VERSION 5.7 ;
  NOWIREEXTENSIONATPIN ON ;
  DIVIDERCHAR "/" ;
  BUSBITCHARS "[]" ;
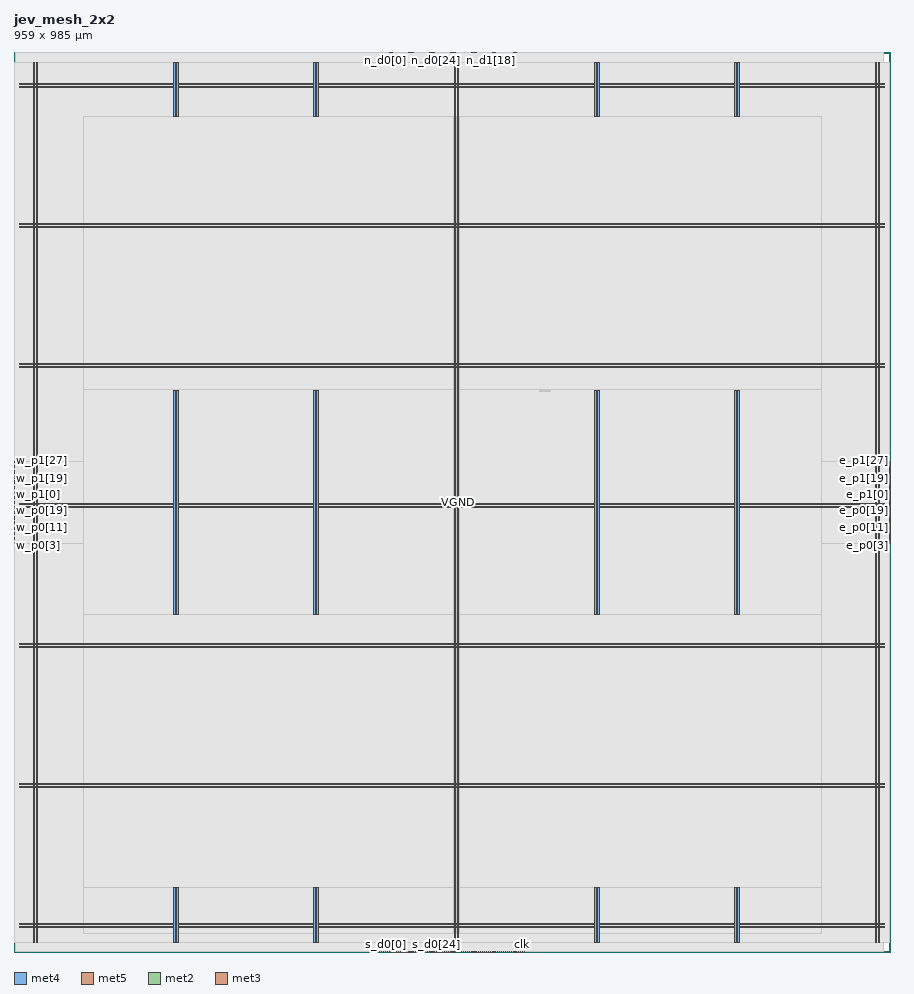
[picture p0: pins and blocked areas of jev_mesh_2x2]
MACRO jev_mesh_2x2
  CLASS BLOCK ;
  FOREIGN jev_mesh_2x2 ;
  ORIGIN 0.000 0.000 ;
  SIZE 959.000 BY 985.000 ;
  PIN VGND
    DIRECTION INOUT ;
    USE GROUND ;
    PORT
      LAYER met4 ;
        RECT 24.340 10.640 25.940 974.000 ;
    END
    PORT
      LAYER met4 ;
        RECT 177.940 10.640 179.540 70.115 ;
    END
    PORT
      LAYER met4 ;
        RECT 177.940 369.845 179.540 614.795 ;
    END
    PORT
      LAYER met4 ;
        RECT 177.940 914.525 179.540 974.000 ;
    END
    PORT
      LAYER met4 ;
        RECT 331.540 10.640 333.140 70.115 ;
    END
    PORT
      LAYER met4 ;
        RECT 331.540 369.845 333.140 614.795 ;
    END
    PORT
      LAYER met4 ;
        RECT 331.540 914.525 333.140 974.000 ;
    END
    PORT
      LAYER met4 ;
        RECT 485.140 10.640 486.740 974.000 ;
    END
    PORT
      LAYER met4 ;
        RECT 638.740 10.640 640.340 70.115 ;
    END
    PORT
      LAYER met4 ;
        RECT 638.740 369.845 640.340 614.795 ;
    END
    PORT
      LAYER met4 ;
        RECT 638.740 914.525 640.340 974.000 ;
    END
    PORT
      LAYER met4 ;
        RECT 792.340 10.640 793.940 70.115 ;
    END
    PORT
      LAYER met4 ;
        RECT 792.340 369.845 793.940 614.795 ;
    END
    PORT
      LAYER met4 ;
        RECT 792.340 914.525 793.940 974.000 ;
    END
    PORT
      LAYER met4 ;
        RECT 945.940 10.640 947.540 974.000 ;
    END
    PORT
      LAYER met5 ;
        RECT 5.520 30.030 953.120 31.630 ;
    END
    PORT
      LAYER met5 ;
        RECT 5.520 183.210 953.120 184.810 ;
    END
    PORT
      LAYER met5 ;
        RECT 5.520 336.390 953.120 337.990 ;
    END
    PORT
      LAYER met5 ;
        RECT 5.520 489.570 953.120 491.170 ;
    END
    PORT
      LAYER met5 ;
        RECT 5.520 642.750 953.120 644.350 ;
    END
    PORT
      LAYER met5 ;
        RECT 5.520 795.930 953.120 797.530 ;
    END
    PORT
      LAYER met5 ;
        RECT 5.520 949.110 953.120 950.710 ;
    END
  END VGND
  PIN VPWR
    DIRECTION INOUT ;
    USE POWER ;
    PORT
      LAYER met4 ;
        RECT 21.040 10.640 22.640 974.000 ;
    END
    PORT
      LAYER met4 ;
        RECT 174.640 10.640 176.240 70.115 ;
    END
    PORT
      LAYER met4 ;
        RECT 174.640 369.845 176.240 614.795 ;
    END
    PORT
      LAYER met4 ;
        RECT 174.640 914.525 176.240 974.000 ;
    END
    PORT
      LAYER met4 ;
        RECT 328.240 10.640 329.840 70.115 ;
    END
    PORT
      LAYER met4 ;
        RECT 328.240 369.845 329.840 614.795 ;
    END
    PORT
      LAYER met4 ;
        RECT 328.240 914.525 329.840 974.000 ;
    END
    PORT
      LAYER met4 ;
        RECT 481.840 10.640 483.440 974.000 ;
    END
    PORT
      LAYER met4 ;
        RECT 635.440 10.640 637.040 70.115 ;
    END
    PORT
      LAYER met4 ;
        RECT 635.440 369.845 637.040 614.795 ;
    END
    PORT
      LAYER met4 ;
        RECT 635.440 914.525 637.040 974.000 ;
    END
    PORT
      LAYER met4 ;
        RECT 789.040 10.640 790.640 70.115 ;
    END
    PORT
      LAYER met4 ;
        RECT 789.040 369.845 790.640 614.795 ;
    END
    PORT
      LAYER met4 ;
        RECT 789.040 914.525 790.640 974.000 ;
    END
    PORT
      LAYER met4 ;
        RECT 942.640 10.640 944.240 974.000 ;
    END
    PORT
      LAYER met5 ;
        RECT 5.520 26.730 953.120 28.330 ;
    END
    PORT
      LAYER met5 ;
        RECT 5.520 179.910 953.120 181.510 ;
    END
    PORT
      LAYER met5 ;
        RECT 5.520 333.090 953.120 334.690 ;
    END
    PORT
      LAYER met5 ;
        RECT 5.520 486.270 953.120 487.870 ;
    END
    PORT
      LAYER met5 ;
        RECT 5.520 639.450 953.120 641.050 ;
    END
    PORT
      LAYER met5 ;
        RECT 5.520 792.630 953.120 794.230 ;
    END
    PORT
      LAYER met5 ;
        RECT 5.520 945.810 953.120 947.410 ;
    END
  END VPWR
  PIN clk
    DIRECTION INPUT ;
    USE SIGNAL ;
    ANTENNAGATEAREA 1.704000 ;
    PORT
      LAYER met2 ;
        RECT 556.230 0.000 556.510 0.280 ;
    END
  END clk
  PIN e_p0[0]
    DIRECTION OUTPUT ;
    USE SIGNAL ;
    ANTENNADIFFAREA 0.383400 ;
    PORT
      LAYER met3 ;
        RECT 958.400 448.840 959.000 449.440 ;
    END
  END e_p0[0]
  PIN e_p0[10]
    DIRECTION OUTPUT ;
    USE SIGNAL ;
    ANTENNADIFFAREA 0.383400 ;
    PORT
      LAYER met3 ;
        RECT 958.400 462.440 959.000 463.040 ;
    END
  END e_p0[10]
  PIN e_p0[11]
    DIRECTION OUTPUT ;
    USE SIGNAL ;
    ANTENNADIFFAREA 0.383400 ;
    PORT
      LAYER met3 ;
        RECT 958.400 463.800 959.000 464.400 ;
    END
  END e_p0[11]
  PIN e_p0[12]
    DIRECTION OUTPUT ;
    USE SIGNAL ;
    ANTENNADIFFAREA 0.383400 ;
    PORT
      LAYER met3 ;
        RECT 958.400 465.160 959.000 465.760 ;
    END
  END e_p0[12]
  PIN e_p0[13]
    DIRECTION OUTPUT ;
    USE SIGNAL ;
    ANTENNADIFFAREA 0.383400 ;
    PORT
      LAYER met3 ;
        RECT 958.400 466.520 959.000 467.120 ;
    END
  END e_p0[13]
  PIN e_p0[14]
    DIRECTION OUTPUT ;
    USE SIGNAL ;
    ANTENNADIFFAREA 0.383400 ;
    PORT
      LAYER met3 ;
        RECT 958.400 467.880 959.000 468.480 ;
    END
  END e_p0[14]
  PIN e_p0[15]
    DIRECTION OUTPUT ;
    USE SIGNAL ;
    ANTENNADIFFAREA 0.383400 ;
    PORT
      LAYER met3 ;
        RECT 958.400 469.240 959.000 469.840 ;
    END
  END e_p0[15]
  PIN e_p0[16]
    DIRECTION OUTPUT ;
    USE SIGNAL ;
    ANTENNADIFFAREA 0.383400 ;
    PORT
      LAYER met3 ;
        RECT 958.400 470.600 959.000 471.200 ;
    END
  END e_p0[16]
  PIN e_p0[17]
    DIRECTION OUTPUT ;
    USE SIGNAL ;
    ANTENNADIFFAREA 0.383400 ;
    PORT
      LAYER met3 ;
        RECT 958.400 471.960 959.000 472.560 ;
    END
  END e_p0[17]
  PIN e_p0[18]
    DIRECTION OUTPUT ;
    USE SIGNAL ;
    ANTENNADIFFAREA 0.383400 ;
    PORT
      LAYER met3 ;
        RECT 958.400 473.320 959.000 473.920 ;
    END
  END e_p0[18]
  PIN e_p0[19]
    DIRECTION OUTPUT ;
    USE SIGNAL ;
    ANTENNADIFFAREA 0.383400 ;
    PORT
      LAYER met3 ;
        RECT 958.400 474.680 959.000 475.280 ;
    END
  END e_p0[19]
  PIN e_p0[1]
    DIRECTION OUTPUT ;
    USE SIGNAL ;
    ANTENNADIFFAREA 0.383400 ;
    PORT
      LAYER met3 ;
        RECT 958.400 450.200 959.000 450.800 ;
    END
  END e_p0[1]
  PIN e_p0[20]
    DIRECTION OUTPUT ;
    USE SIGNAL ;
    ANTENNADIFFAREA 0.383400 ;
    PORT
      LAYER met3 ;
        RECT 958.400 476.040 959.000 476.640 ;
    END
  END e_p0[20]
  PIN e_p0[21]
    DIRECTION OUTPUT ;
    USE SIGNAL ;
    ANTENNADIFFAREA 0.383400 ;
    PORT
      LAYER met3 ;
        RECT 958.400 477.400 959.000 478.000 ;
    END
  END e_p0[21]
  PIN e_p0[22]
    DIRECTION OUTPUT ;
    USE SIGNAL ;
    ANTENNADIFFAREA 0.383400 ;
    PORT
      LAYER met3 ;
        RECT 958.400 478.760 959.000 479.360 ;
    END
  END e_p0[22]
  PIN e_p0[23]
    DIRECTION OUTPUT ;
    USE SIGNAL ;
    ANTENNADIFFAREA 0.383400 ;
    PORT
      LAYER met3 ;
        RECT 958.400 480.120 959.000 480.720 ;
    END
  END e_p0[23]
  PIN e_p0[24]
    DIRECTION OUTPUT ;
    USE SIGNAL ;
    ANTENNADIFFAREA 0.383400 ;
    PORT
      LAYER met3 ;
        RECT 958.400 481.480 959.000 482.080 ;
    END
  END e_p0[24]
  PIN e_p0[25]
    DIRECTION OUTPUT ;
    USE SIGNAL ;
    ANTENNADIFFAREA 0.383400 ;
    PORT
      LAYER met3 ;
        RECT 958.400 482.840 959.000 483.440 ;
    END
  END e_p0[25]
  PIN e_p0[26]
    DIRECTION OUTPUT ;
    USE SIGNAL ;
    ANTENNADIFFAREA 0.383400 ;
    PORT
      LAYER met3 ;
        RECT 958.400 484.200 959.000 484.800 ;
    END
  END e_p0[26]
  PIN e_p0[27]
    DIRECTION OUTPUT ;
    USE SIGNAL ;
    ANTENNADIFFAREA 0.383400 ;
    PORT
      LAYER met3 ;
        RECT 958.400 485.560 959.000 486.160 ;
    END
  END e_p0[27]
  PIN e_p0[28]
    DIRECTION OUTPUT ;
    USE SIGNAL ;
    ANTENNADIFFAREA 0.383400 ;
    PORT
      LAYER met3 ;
        RECT 958.400 486.920 959.000 487.520 ;
    END
  END e_p0[28]
  PIN e_p0[29]
    DIRECTION OUTPUT ;
    USE SIGNAL ;
    ANTENNADIFFAREA 0.383400 ;
    PORT
      LAYER met3 ;
        RECT 958.400 488.280 959.000 488.880 ;
    END
  END e_p0[29]
  PIN e_p0[2]
    DIRECTION OUTPUT ;
    USE SIGNAL ;
    ANTENNADIFFAREA 0.383400 ;
    PORT
      LAYER met3 ;
        RECT 958.400 451.560 959.000 452.160 ;
    END
  END e_p0[2]
  PIN e_p0[30]
    DIRECTION OUTPUT ;
    USE SIGNAL ;
    ANTENNADIFFAREA 0.383400 ;
    PORT
      LAYER met3 ;
        RECT 958.400 489.640 959.000 490.240 ;
    END
  END e_p0[30]
  PIN e_p0[31]
    DIRECTION OUTPUT ;
    USE SIGNAL ;
    ANTENNADIFFAREA 0.383400 ;
    PORT
      LAYER met3 ;
        RECT 958.400 491.000 959.000 491.600 ;
    END
  END e_p0[31]
  PIN e_p0[3]
    DIRECTION OUTPUT ;
    USE SIGNAL ;
    ANTENNADIFFAREA 0.383400 ;
    PORT
      LAYER met3 ;
        RECT 958.400 452.920 959.000 453.520 ;
    END
  END e_p0[3]
  PIN e_p0[4]
    DIRECTION OUTPUT ;
    USE SIGNAL ;
    ANTENNADIFFAREA 0.383400 ;
    PORT
      LAYER met3 ;
        RECT 958.400 454.280 959.000 454.880 ;
    END
  END e_p0[4]
  PIN e_p0[5]
    DIRECTION OUTPUT ;
    USE SIGNAL ;
    ANTENNADIFFAREA 0.383400 ;
    PORT
      LAYER met3 ;
        RECT 958.400 455.640 959.000 456.240 ;
    END
  END e_p0[5]
  PIN e_p0[6]
    DIRECTION OUTPUT ;
    USE SIGNAL ;
    ANTENNADIFFAREA 0.383400 ;
    PORT
      LAYER met3 ;
        RECT 958.400 457.000 959.000 457.600 ;
    END
  END e_p0[6]
  PIN e_p0[7]
    DIRECTION OUTPUT ;
    USE SIGNAL ;
    ANTENNADIFFAREA 0.383400 ;
    PORT
      LAYER met3 ;
        RECT 958.400 458.360 959.000 458.960 ;
    END
  END e_p0[7]
  PIN e_p0[8]
    DIRECTION OUTPUT ;
    USE SIGNAL ;
    ANTENNADIFFAREA 0.383400 ;
    PORT
      LAYER met3 ;
        RECT 958.400 459.720 959.000 460.320 ;
    END
  END e_p0[8]
  PIN e_p0[9]
    DIRECTION OUTPUT ;
    USE SIGNAL ;
    ANTENNADIFFAREA 0.383400 ;
    PORT
      LAYER met3 ;
        RECT 958.400 461.080 959.000 461.680 ;
    END
  END e_p0[9]
  PIN e_p1[0]
    DIRECTION OUTPUT ;
    USE SIGNAL ;
    ANTENNADIFFAREA 0.383400 ;
    PORT
      LAYER met3 ;
        RECT 958.400 492.360 959.000 492.960 ;
    END
  END e_p1[0]
  PIN e_p1[10]
    DIRECTION OUTPUT ;
    USE SIGNAL ;
    ANTENNADIFFAREA 0.383400 ;
    PORT
      LAYER met3 ;
        RECT 958.400 505.960 959.000 506.560 ;
    END
  END e_p1[10]
  PIN e_p1[11]
    DIRECTION OUTPUT ;
    USE SIGNAL ;
    ANTENNADIFFAREA 0.383400 ;
    PORT
      LAYER met3 ;
        RECT 958.400 507.320 959.000 507.920 ;
    END
  END e_p1[11]
  PIN e_p1[12]
    DIRECTION OUTPUT ;
    USE SIGNAL ;
    ANTENNADIFFAREA 0.383400 ;
    PORT
      LAYER met3 ;
        RECT 958.400 508.680 959.000 509.280 ;
    END
  END e_p1[12]
  PIN e_p1[13]
    DIRECTION OUTPUT ;
    USE SIGNAL ;
    ANTENNADIFFAREA 0.383400 ;
    PORT
      LAYER met3 ;
        RECT 958.400 510.040 959.000 510.640 ;
    END
  END e_p1[13]
  PIN e_p1[14]
    DIRECTION OUTPUT ;
    USE SIGNAL ;
    ANTENNADIFFAREA 0.383400 ;
    PORT
      LAYER met3 ;
        RECT 958.400 511.400 959.000 512.000 ;
    END
  END e_p1[14]
  PIN e_p1[15]
    DIRECTION OUTPUT ;
    USE SIGNAL ;
    ANTENNADIFFAREA 0.383400 ;
    PORT
      LAYER met3 ;
        RECT 958.400 512.760 959.000 513.360 ;
    END
  END e_p1[15]
  PIN e_p1[16]
    DIRECTION OUTPUT ;
    USE SIGNAL ;
    ANTENNADIFFAREA 0.383400 ;
    PORT
      LAYER met3 ;
        RECT 958.400 514.120 959.000 514.720 ;
    END
  END e_p1[16]
  PIN e_p1[17]
    DIRECTION OUTPUT ;
    USE SIGNAL ;
    ANTENNADIFFAREA 0.383400 ;
    PORT
      LAYER met3 ;
        RECT 958.400 515.480 959.000 516.080 ;
    END
  END e_p1[17]
  PIN e_p1[18]
    DIRECTION OUTPUT ;
    USE SIGNAL ;
    ANTENNADIFFAREA 0.383400 ;
    PORT
      LAYER met3 ;
        RECT 958.400 516.840 959.000 517.440 ;
    END
  END e_p1[18]
  PIN e_p1[19]
    DIRECTION OUTPUT ;
    USE SIGNAL ;
    ANTENNADIFFAREA 0.383400 ;
    PORT
      LAYER met3 ;
        RECT 958.400 518.200 959.000 518.800 ;
    END
  END e_p1[19]
  PIN e_p1[1]
    DIRECTION OUTPUT ;
    USE SIGNAL ;
    ANTENNADIFFAREA 0.383400 ;
    PORT
      LAYER met3 ;
        RECT 958.400 493.720 959.000 494.320 ;
    END
  END e_p1[1]
  PIN e_p1[20]
    DIRECTION OUTPUT ;
    USE SIGNAL ;
    ANTENNADIFFAREA 0.383400 ;
    PORT
      LAYER met3 ;
        RECT 958.400 519.560 959.000 520.160 ;
    END
  END e_p1[20]
  PIN e_p1[21]
    DIRECTION OUTPUT ;
    USE SIGNAL ;
    ANTENNADIFFAREA 0.383400 ;
    PORT
      LAYER met3 ;
        RECT 958.400 520.920 959.000 521.520 ;
    END
  END e_p1[21]
  PIN e_p1[22]
    DIRECTION OUTPUT ;
    USE SIGNAL ;
    ANTENNADIFFAREA 0.383400 ;
    PORT
      LAYER met3 ;
        RECT 958.400 522.280 959.000 522.880 ;
    END
  END e_p1[22]
  PIN e_p1[23]
    DIRECTION OUTPUT ;
    USE SIGNAL ;
    ANTENNADIFFAREA 0.383400 ;
    PORT
      LAYER met3 ;
        RECT 958.400 523.640 959.000 524.240 ;
    END
  END e_p1[23]
  PIN e_p1[24]
    DIRECTION OUTPUT ;
    USE SIGNAL ;
    ANTENNADIFFAREA 0.383400 ;
    PORT
      LAYER met3 ;
        RECT 958.400 525.000 959.000 525.600 ;
    END
  END e_p1[24]
  PIN e_p1[25]
    DIRECTION OUTPUT ;
    USE SIGNAL ;
    ANTENNADIFFAREA 0.383400 ;
    PORT
      LAYER met3 ;
        RECT 958.400 526.360 959.000 526.960 ;
    END
  END e_p1[25]
  PIN e_p1[26]
    DIRECTION OUTPUT ;
    USE SIGNAL ;
    ANTENNADIFFAREA 0.383400 ;
    PORT
      LAYER met3 ;
        RECT 958.400 527.720 959.000 528.320 ;
    END
  END e_p1[26]
  PIN e_p1[27]
    DIRECTION OUTPUT ;
    USE SIGNAL ;
    ANTENNADIFFAREA 0.383400 ;
    PORT
      LAYER met3 ;
        RECT 958.400 529.080 959.000 529.680 ;
    END
  END e_p1[27]
  PIN e_p1[28]
    DIRECTION OUTPUT ;
    USE SIGNAL ;
    ANTENNADIFFAREA 0.383400 ;
    PORT
      LAYER met3 ;
        RECT 958.400 530.440 959.000 531.040 ;
    END
  END e_p1[28]
  PIN e_p1[29]
    DIRECTION OUTPUT ;
    USE SIGNAL ;
    ANTENNADIFFAREA 0.383400 ;
    PORT
      LAYER met3 ;
        RECT 958.400 531.800 959.000 532.400 ;
    END
  END e_p1[29]
  PIN e_p1[2]
    DIRECTION OUTPUT ;
    USE SIGNAL ;
    ANTENNADIFFAREA 0.383400 ;
    PORT
      LAYER met3 ;
        RECT 958.400 495.080 959.000 495.680 ;
    END
  END e_p1[2]
  PIN e_p1[30]
    DIRECTION OUTPUT ;
    USE SIGNAL ;
    ANTENNADIFFAREA 0.383400 ;
    PORT
      LAYER met3 ;
        RECT 958.400 533.160 959.000 533.760 ;
    END
  END e_p1[30]
  PIN e_p1[31]
    DIRECTION OUTPUT ;
    USE SIGNAL ;
    ANTENNADIFFAREA 0.383400 ;
    PORT
      LAYER met3 ;
        RECT 958.400 534.520 959.000 535.120 ;
    END
  END e_p1[31]
  PIN e_p1[3]
    DIRECTION OUTPUT ;
    USE SIGNAL ;
    ANTENNADIFFAREA 0.383400 ;
    PORT
      LAYER met3 ;
        RECT 958.400 496.440 959.000 497.040 ;
    END
  END e_p1[3]
  PIN e_p1[4]
    DIRECTION OUTPUT ;
    USE SIGNAL ;
    ANTENNADIFFAREA 0.383400 ;
    PORT
      LAYER met3 ;
        RECT 958.400 497.800 959.000 498.400 ;
    END
  END e_p1[4]
  PIN e_p1[5]
    DIRECTION OUTPUT ;
    USE SIGNAL ;
    ANTENNADIFFAREA 0.383400 ;
    PORT
      LAYER met3 ;
        RECT 958.400 499.160 959.000 499.760 ;
    END
  END e_p1[5]
  PIN e_p1[6]
    DIRECTION OUTPUT ;
    USE SIGNAL ;
    ANTENNADIFFAREA 0.383400 ;
    PORT
      LAYER met3 ;
        RECT 958.400 500.520 959.000 501.120 ;
    END
  END e_p1[6]
  PIN e_p1[7]
    DIRECTION OUTPUT ;
    USE SIGNAL ;
    ANTENNADIFFAREA 0.383400 ;
    PORT
      LAYER met3 ;
        RECT 958.400 501.880 959.000 502.480 ;
    END
  END e_p1[7]
  PIN e_p1[8]
    DIRECTION OUTPUT ;
    USE SIGNAL ;
    ANTENNADIFFAREA 0.383400 ;
    PORT
      LAYER met3 ;
        RECT 958.400 503.240 959.000 503.840 ;
    END
  END e_p1[8]
  PIN e_p1[9]
    DIRECTION OUTPUT ;
    USE SIGNAL ;
    ANTENNADIFFAREA 0.383400 ;
    PORT
      LAYER met3 ;
        RECT 958.400 504.600 959.000 505.200 ;
    END
  END e_p1[9]
  PIN e_ready
    DIRECTION INPUT ;
    USE SIGNAL ;
    ANTENNAGATEAREA 0.213000 ;
    PORT
      LAYER met3 ;
        RECT 958.400 535.880 959.000 536.480 ;
    END
  END e_ready
  PIN e_valid
    DIRECTION OUTPUT ;
    USE SIGNAL ;
    ANTENNADIFFAREA 0.383400 ;
    PORT
      LAYER met3 ;
        RECT 958.400 447.480 959.000 448.080 ;
    END
  END e_valid
  PIN n_d0[0]
    DIRECTION INPUT ;
    USE SIGNAL ;
    ANTENNAGATEAREA 0.213000 ;
    PORT
      LAYER met2 ;
        RECT 406.730 984.720 407.010 985.000 ;
    END
  END n_d0[0]
  PIN n_d0[10]
    DIRECTION INPUT ;
    USE SIGNAL ;
    ANTENNAGATEAREA 0.213000 ;
    PORT
      LAYER met2 ;
        RECT 429.730 984.720 430.010 985.000 ;
    END
  END n_d0[10]
  PIN n_d0[11]
    DIRECTION INPUT ;
    USE SIGNAL ;
    ANTENNAGATEAREA 0.213000 ;
    PORT
      LAYER met2 ;
        RECT 432.030 984.720 432.310 985.000 ;
    END
  END n_d0[11]
  PIN n_d0[12]
    DIRECTION INPUT ;
    USE SIGNAL ;
    ANTENNAGATEAREA 0.213000 ;
    PORT
      LAYER met2 ;
        RECT 434.330 984.720 434.610 985.000 ;
    END
  END n_d0[12]
  PIN n_d0[13]
    DIRECTION INPUT ;
    USE SIGNAL ;
    ANTENNAGATEAREA 0.213000 ;
    PORT
      LAYER met2 ;
        RECT 436.630 984.720 436.910 985.000 ;
    END
  END n_d0[13]
  PIN n_d0[14]
    DIRECTION INPUT ;
    USE SIGNAL ;
    ANTENNAGATEAREA 0.213000 ;
    PORT
      LAYER met2 ;
        RECT 438.930 984.720 439.210 985.000 ;
    END
  END n_d0[14]
  PIN n_d0[15]
    DIRECTION INPUT ;
    USE SIGNAL ;
    ANTENNAGATEAREA 0.213000 ;
    PORT
      LAYER met2 ;
        RECT 441.230 984.720 441.510 985.000 ;
    END
  END n_d0[15]
  PIN n_d0[16]
    DIRECTION INPUT ;
    USE SIGNAL ;
    ANTENNAGATEAREA 0.213000 ;
    PORT
      LAYER met2 ;
        RECT 443.530 984.720 443.810 985.000 ;
    END
  END n_d0[16]
  PIN n_d0[17]
    DIRECTION INPUT ;
    USE SIGNAL ;
    ANTENNAGATEAREA 0.213000 ;
    PORT
      LAYER met2 ;
        RECT 445.830 984.720 446.110 985.000 ;
    END
  END n_d0[17]
  PIN n_d0[18]
    DIRECTION INPUT ;
    USE SIGNAL ;
    ANTENNAGATEAREA 0.213000 ;
    PORT
      LAYER met2 ;
        RECT 448.130 984.720 448.410 985.000 ;
    END
  END n_d0[18]
  PIN n_d0[19]
    DIRECTION INPUT ;
    USE SIGNAL ;
    ANTENNAGATEAREA 0.213000 ;
    PORT
      LAYER met2 ;
        RECT 450.430 984.720 450.710 985.000 ;
    END
  END n_d0[19]
  PIN n_d0[1]
    DIRECTION INPUT ;
    USE SIGNAL ;
    ANTENNAGATEAREA 0.213000 ;
    PORT
      LAYER met2 ;
        RECT 409.030 984.720 409.310 985.000 ;
    END
  END n_d0[1]
  PIN n_d0[20]
    DIRECTION INPUT ;
    USE SIGNAL ;
    ANTENNAGATEAREA 0.213000 ;
    PORT
      LAYER met2 ;
        RECT 452.730 984.720 453.010 985.000 ;
    END
  END n_d0[20]
  PIN n_d0[21]
    DIRECTION INPUT ;
    USE SIGNAL ;
    ANTENNAGATEAREA 0.213000 ;
    PORT
      LAYER met2 ;
        RECT 455.030 984.720 455.310 985.000 ;
    END
  END n_d0[21]
  PIN n_d0[22]
    DIRECTION INPUT ;
    USE SIGNAL ;
    ANTENNAGATEAREA 0.213000 ;
    PORT
      LAYER met2 ;
        RECT 457.330 984.720 457.610 985.000 ;
    END
  END n_d0[22]
  PIN n_d0[23]
    DIRECTION INPUT ;
    USE SIGNAL ;
    ANTENNAGATEAREA 0.213000 ;
    PORT
      LAYER met2 ;
        RECT 459.630 984.720 459.910 985.000 ;
    END
  END n_d0[23]
  PIN n_d0[24]
    DIRECTION INPUT ;
    USE SIGNAL ;
    ANTENNAGATEAREA 0.213000 ;
    PORT
      LAYER met2 ;
        RECT 461.930 984.720 462.210 985.000 ;
    END
  END n_d0[24]
  PIN n_d0[25]
    DIRECTION INPUT ;
    USE SIGNAL ;
    ANTENNAGATEAREA 0.213000 ;
    PORT
      LAYER met2 ;
        RECT 464.230 984.720 464.510 985.000 ;
    END
  END n_d0[25]
  PIN n_d0[26]
    DIRECTION INPUT ;
    USE SIGNAL ;
    ANTENNAGATEAREA 0.213000 ;
    PORT
      LAYER met2 ;
        RECT 466.530 984.720 466.810 985.000 ;
    END
  END n_d0[26]
  PIN n_d0[27]
    DIRECTION INPUT ;
    USE SIGNAL ;
    ANTENNAGATEAREA 0.213000 ;
    PORT
      LAYER met2 ;
        RECT 468.830 984.720 469.110 985.000 ;
    END
  END n_d0[27]
  PIN n_d0[28]
    DIRECTION INPUT ;
    USE SIGNAL ;
    ANTENNAGATEAREA 0.213000 ;
    PORT
      LAYER met2 ;
        RECT 471.130 984.720 471.410 985.000 ;
    END
  END n_d0[28]
  PIN n_d0[29]
    DIRECTION INPUT ;
    USE SIGNAL ;
    ANTENNAGATEAREA 0.213000 ;
    PORT
      LAYER met2 ;
        RECT 473.430 984.720 473.710 985.000 ;
    END
  END n_d0[29]
  PIN n_d0[2]
    DIRECTION INPUT ;
    USE SIGNAL ;
    ANTENNAGATEAREA 0.213000 ;
    PORT
      LAYER met2 ;
        RECT 411.330 984.720 411.610 985.000 ;
    END
  END n_d0[2]
  PIN n_d0[30]
    DIRECTION INPUT ;
    USE SIGNAL ;
    ANTENNAGATEAREA 0.213000 ;
    PORT
      LAYER met2 ;
        RECT 475.730 984.720 476.010 985.000 ;
    END
  END n_d0[30]
  PIN n_d0[31]
    DIRECTION INPUT ;
    USE SIGNAL ;
    ANTENNAGATEAREA 0.213000 ;
    PORT
      LAYER met2 ;
        RECT 478.030 984.720 478.310 985.000 ;
    END
  END n_d0[31]
  PIN n_d0[3]
    DIRECTION INPUT ;
    USE SIGNAL ;
    ANTENNAGATEAREA 0.213000 ;
    PORT
      LAYER met2 ;
        RECT 413.630 984.720 413.910 985.000 ;
    END
  END n_d0[3]
  PIN n_d0[4]
    DIRECTION INPUT ;
    USE SIGNAL ;
    ANTENNAGATEAREA 0.213000 ;
    PORT
      LAYER met2 ;
        RECT 415.930 984.720 416.210 985.000 ;
    END
  END n_d0[4]
  PIN n_d0[5]
    DIRECTION INPUT ;
    USE SIGNAL ;
    ANTENNAGATEAREA 0.213000 ;
    PORT
      LAYER met2 ;
        RECT 418.230 984.720 418.510 985.000 ;
    END
  END n_d0[5]
  PIN n_d0[6]
    DIRECTION INPUT ;
    USE SIGNAL ;
    ANTENNAGATEAREA 0.213000 ;
    PORT
      LAYER met2 ;
        RECT 420.530 984.720 420.810 985.000 ;
    END
  END n_d0[6]
  PIN n_d0[7]
    DIRECTION INPUT ;
    USE SIGNAL ;
    ANTENNAGATEAREA 0.213000 ;
    PORT
      LAYER met2 ;
        RECT 422.830 984.720 423.110 985.000 ;
    END
  END n_d0[7]
  PIN n_d0[8]
    DIRECTION INPUT ;
    USE SIGNAL ;
    ANTENNAGATEAREA 0.213000 ;
    PORT
      LAYER met2 ;
        RECT 425.130 984.720 425.410 985.000 ;
    END
  END n_d0[8]
  PIN n_d0[9]
    DIRECTION INPUT ;
    USE SIGNAL ;
    ANTENNAGATEAREA 0.213000 ;
    PORT
      LAYER met2 ;
        RECT 427.430 984.720 427.710 985.000 ;
    END
  END n_d0[9]
  PIN n_d1[0]
    DIRECTION INPUT ;
    USE SIGNAL ;
    ANTENNAGATEAREA 0.213000 ;
    PORT
      LAYER met2 ;
        RECT 480.330 984.720 480.610 985.000 ;
    END
  END n_d1[0]
  PIN n_d1[10]
    DIRECTION INPUT ;
    USE SIGNAL ;
    ANTENNAGATEAREA 0.213000 ;
    PORT
      LAYER met2 ;
        RECT 503.330 984.720 503.610 985.000 ;
    END
  END n_d1[10]
  PIN n_d1[11]
    DIRECTION INPUT ;
    USE SIGNAL ;
    ANTENNAGATEAREA 0.213000 ;
    PORT
      LAYER met2 ;
        RECT 505.630 984.720 505.910 985.000 ;
    END
  END n_d1[11]
  PIN n_d1[12]
    DIRECTION INPUT ;
    USE SIGNAL ;
    ANTENNAGATEAREA 0.213000 ;
    PORT
      LAYER met2 ;
        RECT 507.930 984.720 508.210 985.000 ;
    END
  END n_d1[12]
  PIN n_d1[13]
    DIRECTION INPUT ;
    USE SIGNAL ;
    ANTENNAGATEAREA 0.213000 ;
    PORT
      LAYER met2 ;
        RECT 510.230 984.720 510.510 985.000 ;
    END
  END n_d1[13]
  PIN n_d1[14]
    DIRECTION INPUT ;
    USE SIGNAL ;
    ANTENNAGATEAREA 0.213000 ;
    PORT
      LAYER met2 ;
        RECT 512.530 984.720 512.810 985.000 ;
    END
  END n_d1[14]
  PIN n_d1[15]
    DIRECTION INPUT ;
    USE SIGNAL ;
    ANTENNAGATEAREA 0.213000 ;
    PORT
      LAYER met2 ;
        RECT 514.830 984.720 515.110 985.000 ;
    END
  END n_d1[15]
  PIN n_d1[16]
    DIRECTION INPUT ;
    USE SIGNAL ;
    ANTENNAGATEAREA 0.213000 ;
    PORT
      LAYER met2 ;
        RECT 517.130 984.720 517.410 985.000 ;
    END
  END n_d1[16]
  PIN n_d1[17]
    DIRECTION INPUT ;
    USE SIGNAL ;
    ANTENNAGATEAREA 0.213000 ;
    PORT
      LAYER met2 ;
        RECT 519.430 984.720 519.710 985.000 ;
    END
  END n_d1[17]
  PIN n_d1[18]
    DIRECTION INPUT ;
    USE SIGNAL ;
    ANTENNAGATEAREA 0.213000 ;
    PORT
      LAYER met2 ;
        RECT 521.730 984.720 522.010 985.000 ;
    END
  END n_d1[18]
  PIN n_d1[19]
    DIRECTION INPUT ;
    USE SIGNAL ;
    ANTENNAGATEAREA 0.213000 ;
    PORT
      LAYER met2 ;
        RECT 524.030 984.720 524.310 985.000 ;
    END
  END n_d1[19]
  PIN n_d1[1]
    DIRECTION INPUT ;
    USE SIGNAL ;
    ANTENNAGATEAREA 0.213000 ;
    PORT
      LAYER met2 ;
        RECT 482.630 984.720 482.910 985.000 ;
    END
  END n_d1[1]
  PIN n_d1[20]
    DIRECTION INPUT ;
    USE SIGNAL ;
    ANTENNAGATEAREA 0.213000 ;
    PORT
      LAYER met2 ;
        RECT 526.330 984.720 526.610 985.000 ;
    END
  END n_d1[20]
  PIN n_d1[21]
    DIRECTION INPUT ;
    USE SIGNAL ;
    ANTENNAGATEAREA 0.213000 ;
    PORT
      LAYER met2 ;
        RECT 528.630 984.720 528.910 985.000 ;
    END
  END n_d1[21]
  PIN n_d1[22]
    DIRECTION INPUT ;
    USE SIGNAL ;
    ANTENNAGATEAREA 0.213000 ;
    PORT
      LAYER met2 ;
        RECT 530.930 984.720 531.210 985.000 ;
    END
  END n_d1[22]
  PIN n_d1[23]
    DIRECTION INPUT ;
    USE SIGNAL ;
    ANTENNAGATEAREA 0.213000 ;
    PORT
      LAYER met2 ;
        RECT 533.230 984.720 533.510 985.000 ;
    END
  END n_d1[23]
  PIN n_d1[24]
    DIRECTION INPUT ;
    USE SIGNAL ;
    ANTENNAGATEAREA 0.213000 ;
    PORT
      LAYER met2 ;
        RECT 535.530 984.720 535.810 985.000 ;
    END
  END n_d1[24]
  PIN n_d1[25]
    DIRECTION INPUT ;
    USE SIGNAL ;
    ANTENNAGATEAREA 0.213000 ;
    PORT
      LAYER met2 ;
        RECT 537.830 984.720 538.110 985.000 ;
    END
  END n_d1[25]
  PIN n_d1[26]
    DIRECTION INPUT ;
    USE SIGNAL ;
    ANTENNAGATEAREA 0.213000 ;
    PORT
      LAYER met2 ;
        RECT 540.130 984.720 540.410 985.000 ;
    END
  END n_d1[26]
  PIN n_d1[27]
    DIRECTION INPUT ;
    USE SIGNAL ;
    ANTENNAGATEAREA 0.213000 ;
    PORT
      LAYER met2 ;
        RECT 542.430 984.720 542.710 985.000 ;
    END
  END n_d1[27]
  PIN n_d1[28]
    DIRECTION INPUT ;
    USE SIGNAL ;
    ANTENNAGATEAREA 0.213000 ;
    PORT
      LAYER met2 ;
        RECT 544.730 984.720 545.010 985.000 ;
    END
  END n_d1[28]
  PIN n_d1[29]
    DIRECTION INPUT ;
    USE SIGNAL ;
    ANTENNAGATEAREA 0.159000 ;
    PORT
      LAYER met2 ;
        RECT 547.030 984.720 547.310 985.000 ;
    END
  END n_d1[29]
  PIN n_d1[2]
    DIRECTION INPUT ;
    USE SIGNAL ;
    ANTENNAGATEAREA 0.213000 ;
    PORT
      LAYER met2 ;
        RECT 484.930 984.720 485.210 985.000 ;
    END
  END n_d1[2]
  PIN n_d1[30]
    DIRECTION INPUT ;
    USE SIGNAL ;
    ANTENNAGATEAREA 0.213000 ;
    PORT
      LAYER met2 ;
        RECT 549.330 984.720 549.610 985.000 ;
    END
  END n_d1[30]
  PIN n_d1[31]
    DIRECTION INPUT ;
    USE SIGNAL ;
    ANTENNAGATEAREA 0.159000 ;
    PORT
      LAYER met2 ;
        RECT 551.630 984.720 551.910 985.000 ;
    END
  END n_d1[31]
  PIN n_d1[3]
    DIRECTION INPUT ;
    USE SIGNAL ;
    ANTENNAGATEAREA 0.213000 ;
    PORT
      LAYER met2 ;
        RECT 487.230 984.720 487.510 985.000 ;
    END
  END n_d1[3]
  PIN n_d1[4]
    DIRECTION INPUT ;
    USE SIGNAL ;
    ANTENNAGATEAREA 0.213000 ;
    PORT
      LAYER met2 ;
        RECT 489.530 984.720 489.810 985.000 ;
    END
  END n_d1[4]
  PIN n_d1[5]
    DIRECTION INPUT ;
    USE SIGNAL ;
    ANTENNAGATEAREA 0.213000 ;
    PORT
      LAYER met2 ;
        RECT 491.830 984.720 492.110 985.000 ;
    END
  END n_d1[5]
  PIN n_d1[6]
    DIRECTION INPUT ;
    USE SIGNAL ;
    ANTENNAGATEAREA 0.213000 ;
    PORT
      LAYER met2 ;
        RECT 494.130 984.720 494.410 985.000 ;
    END
  END n_d1[6]
  PIN n_d1[7]
    DIRECTION INPUT ;
    USE SIGNAL ;
    ANTENNAGATEAREA 0.213000 ;
    PORT
      LAYER met2 ;
        RECT 496.430 984.720 496.710 985.000 ;
    END
  END n_d1[7]
  PIN n_d1[8]
    DIRECTION INPUT ;
    USE SIGNAL ;
    ANTENNAGATEAREA 0.213000 ;
    PORT
      LAYER met2 ;
        RECT 498.730 984.720 499.010 985.000 ;
    END
  END n_d1[8]
  PIN n_d1[9]
    DIRECTION INPUT ;
    USE SIGNAL ;
    ANTENNAGATEAREA 0.213000 ;
    PORT
      LAYER met2 ;
        RECT 501.030 984.720 501.310 985.000 ;
    END
  END n_d1[9]
  PIN n_kind[0]
    DIRECTION INPUT ;
    USE SIGNAL ;
    ANTENNAGATEAREA 0.213000 ;
    PORT
      LAYER met2 ;
        RECT 402.130 984.720 402.410 985.000 ;
    END
  END n_kind[0]
  PIN n_kind[1]
    DIRECTION INPUT ;
    USE SIGNAL ;
    ANTENNAGATEAREA 0.213000 ;
    PORT
      LAYER met2 ;
        RECT 404.430 984.720 404.710 985.000 ;
    END
  END n_kind[1]
  PIN n_ready
    DIRECTION OUTPUT ;
    USE SIGNAL ;
    ANTENNADIFFAREA 0.383400 ;
    PORT
      LAYER met2 ;
        RECT 553.930 984.720 554.210 985.000 ;
    END
  END n_ready
  PIN n_valid
    DIRECTION INPUT ;
    USE SIGNAL ;
    ANTENNAGATEAREA 0.213000 ;
    PORT
      LAYER met2 ;
        RECT 399.830 984.720 400.110 985.000 ;
    END
  END n_valid
  PIN rst
    DIRECTION INPUT ;
    USE SIGNAL ;
    ANTENNAGATEAREA 0.159000 ;
    PORT
      LAYER met2 ;
        RECT 558.530 0.000 558.810 0.280 ;
    END
  END rst
  PIN s_d0[0]
    DIRECTION OUTPUT ;
    USE SIGNAL ;
    ANTENNADIFFAREA 0.383400 ;
    PORT
      LAYER met2 ;
        RECT 406.730 0.000 407.010 0.280 ;
    END
  END s_d0[0]
  PIN s_d0[10]
    DIRECTION OUTPUT ;
    USE SIGNAL ;
    ANTENNADIFFAREA 0.383400 ;
    PORT
      LAYER met2 ;
        RECT 429.730 0.000 430.010 0.280 ;
    END
  END s_d0[10]
  PIN s_d0[11]
    DIRECTION OUTPUT ;
    USE SIGNAL ;
    ANTENNADIFFAREA 0.383400 ;
    PORT
      LAYER met2 ;
        RECT 432.030 0.000 432.310 0.280 ;
    END
  END s_d0[11]
  PIN s_d0[12]
    DIRECTION OUTPUT ;
    USE SIGNAL ;
    ANTENNADIFFAREA 0.383400 ;
    PORT
      LAYER met2 ;
        RECT 434.330 0.000 434.610 0.280 ;
    END
  END s_d0[12]
  PIN s_d0[13]
    DIRECTION OUTPUT ;
    USE SIGNAL ;
    ANTENNADIFFAREA 0.383400 ;
    PORT
      LAYER met2 ;
        RECT 436.630 0.000 436.910 0.280 ;
    END
  END s_d0[13]
  PIN s_d0[14]
    DIRECTION OUTPUT ;
    USE SIGNAL ;
    ANTENNADIFFAREA 0.383400 ;
    PORT
      LAYER met2 ;
        RECT 438.930 0.000 439.210 0.280 ;
    END
  END s_d0[14]
  PIN s_d0[15]
    DIRECTION OUTPUT ;
    USE SIGNAL ;
    ANTENNADIFFAREA 0.383400 ;
    PORT
      LAYER met2 ;
        RECT 441.230 0.000 441.510 0.280 ;
    END
  END s_d0[15]
  PIN s_d0[16]
    DIRECTION OUTPUT ;
    USE SIGNAL ;
    ANTENNADIFFAREA 0.383400 ;
    PORT
      LAYER met2 ;
        RECT 443.530 0.000 443.810 0.280 ;
    END
  END s_d0[16]
  PIN s_d0[17]
    DIRECTION OUTPUT ;
    USE SIGNAL ;
    ANTENNADIFFAREA 0.383400 ;
    PORT
      LAYER met2 ;
        RECT 445.830 0.000 446.110 0.280 ;
    END
  END s_d0[17]
  PIN s_d0[18]
    DIRECTION OUTPUT ;
    USE SIGNAL ;
    ANTENNADIFFAREA 0.383400 ;
    PORT
      LAYER met2 ;
        RECT 448.130 0.000 448.410 0.280 ;
    END
  END s_d0[18]
  PIN s_d0[19]
    DIRECTION OUTPUT ;
    USE SIGNAL ;
    ANTENNADIFFAREA 0.383400 ;
    PORT
      LAYER met2 ;
        RECT 450.430 0.000 450.710 0.280 ;
    END
  END s_d0[19]
  PIN s_d0[1]
    DIRECTION OUTPUT ;
    USE SIGNAL ;
    ANTENNADIFFAREA 0.383400 ;
    PORT
      LAYER met2 ;
        RECT 409.030 0.000 409.310 0.280 ;
    END
  END s_d0[1]
  PIN s_d0[20]
    DIRECTION OUTPUT ;
    USE SIGNAL ;
    ANTENNADIFFAREA 0.383400 ;
    PORT
      LAYER met2 ;
        RECT 452.730 0.000 453.010 0.280 ;
    END
  END s_d0[20]
  PIN s_d0[21]
    DIRECTION OUTPUT ;
    USE SIGNAL ;
    ANTENNADIFFAREA 0.383400 ;
    PORT
      LAYER met2 ;
        RECT 455.030 0.000 455.310 0.280 ;
    END
  END s_d0[21]
  PIN s_d0[22]
    DIRECTION OUTPUT ;
    USE SIGNAL ;
    ANTENNADIFFAREA 0.383400 ;
    PORT
      LAYER met2 ;
        RECT 457.330 0.000 457.610 0.280 ;
    END
  END s_d0[22]
  PIN s_d0[23]
    DIRECTION OUTPUT ;
    USE SIGNAL ;
    ANTENNADIFFAREA 0.383400 ;
    PORT
      LAYER met2 ;
        RECT 459.630 0.000 459.910 0.280 ;
    END
  END s_d0[23]
  PIN s_d0[24]
    DIRECTION OUTPUT ;
    USE SIGNAL ;
    ANTENNADIFFAREA 0.383400 ;
    PORT
      LAYER met2 ;
        RECT 461.930 0.000 462.210 0.280 ;
    END
  END s_d0[24]
  PIN s_d0[25]
    DIRECTION OUTPUT ;
    USE SIGNAL ;
    ANTENNADIFFAREA 0.383400 ;
    PORT
      LAYER met2 ;
        RECT 464.230 0.000 464.510 0.280 ;
    END
  END s_d0[25]
  PIN s_d0[26]
    DIRECTION OUTPUT ;
    USE SIGNAL ;
    ANTENNADIFFAREA 0.383400 ;
    PORT
      LAYER met2 ;
        RECT 466.530 0.000 466.810 0.280 ;
    END
  END s_d0[26]
  PIN s_d0[27]
    DIRECTION OUTPUT ;
    USE SIGNAL ;
    ANTENNADIFFAREA 0.383400 ;
    PORT
      LAYER met2 ;
        RECT 468.830 0.000 469.110 0.280 ;
    END
  END s_d0[27]
  PIN s_d0[28]
    DIRECTION OUTPUT ;
    USE SIGNAL ;
    ANTENNADIFFAREA 0.383400 ;
    PORT
      LAYER met2 ;
        RECT 471.130 0.000 471.410 0.280 ;
    END
  END s_d0[28]
  PIN s_d0[29]
    DIRECTION OUTPUT ;
    USE SIGNAL ;
    ANTENNADIFFAREA 0.383400 ;
    PORT
      LAYER met2 ;
        RECT 473.430 0.000 473.710 0.280 ;
    END
  END s_d0[29]
  PIN s_d0[2]
    DIRECTION OUTPUT ;
    USE SIGNAL ;
    ANTENNADIFFAREA 0.383400 ;
    PORT
      LAYER met2 ;
        RECT 411.330 0.000 411.610 0.280 ;
    END
  END s_d0[2]
  PIN s_d0[30]
    DIRECTION OUTPUT ;
    USE SIGNAL ;
    ANTENNADIFFAREA 0.383400 ;
    PORT
      LAYER met2 ;
        RECT 475.730 0.000 476.010 0.280 ;
    END
  END s_d0[30]
  PIN s_d0[31]
    DIRECTION OUTPUT ;
    USE SIGNAL ;
    ANTENNADIFFAREA 0.383400 ;
    PORT
      LAYER met2 ;
        RECT 478.030 0.000 478.310 0.280 ;
    END
  END s_d0[31]
  PIN s_d0[3]
    DIRECTION OUTPUT ;
    USE SIGNAL ;
    ANTENNADIFFAREA 0.383400 ;
    PORT
      LAYER met2 ;
        RECT 413.630 0.000 413.910 0.280 ;
    END
  END s_d0[3]
  PIN s_d0[4]
    DIRECTION OUTPUT ;
    USE SIGNAL ;
    ANTENNADIFFAREA 0.383400 ;
    PORT
      LAYER met2 ;
        RECT 415.930 0.000 416.210 0.280 ;
    END
  END s_d0[4]
  PIN s_d0[5]
    DIRECTION OUTPUT ;
    USE SIGNAL ;
    ANTENNADIFFAREA 0.383400 ;
    PORT
      LAYER met2 ;
        RECT 418.230 0.000 418.510 0.280 ;
    END
  END s_d0[5]
  PIN s_d0[6]
    DIRECTION OUTPUT ;
    USE SIGNAL ;
    ANTENNADIFFAREA 0.383400 ;
    PORT
      LAYER met2 ;
        RECT 420.530 0.000 420.810 0.280 ;
    END
  END s_d0[6]
  PIN s_d0[7]
    DIRECTION OUTPUT ;
    USE SIGNAL ;
    ANTENNADIFFAREA 0.383400 ;
    PORT
      LAYER met2 ;
        RECT 422.830 0.000 423.110 0.280 ;
    END
  END s_d0[7]
  PIN s_d0[8]
    DIRECTION OUTPUT ;
    USE SIGNAL ;
    ANTENNADIFFAREA 0.383400 ;
    PORT
      LAYER met2 ;
        RECT 425.130 0.000 425.410 0.280 ;
    END
  END s_d0[8]
  PIN s_d0[9]
    DIRECTION OUTPUT ;
    USE SIGNAL ;
    ANTENNADIFFAREA 0.383400 ;
    PORT
      LAYER met2 ;
        RECT 427.430 0.000 427.710 0.280 ;
    END
  END s_d0[9]
  PIN s_d1[0]
    DIRECTION OUTPUT ;
    USE SIGNAL ;
    ANTENNADIFFAREA 0.383400 ;
    PORT
      LAYER met2 ;
        RECT 480.330 0.000 480.610 0.280 ;
    END
  END s_d1[0]
  PIN s_d1[10]
    DIRECTION OUTPUT ;
    USE SIGNAL ;
    ANTENNADIFFAREA 0.383400 ;
    PORT
      LAYER met2 ;
        RECT 503.330 0.000 503.610 0.280 ;
    END
  END s_d1[10]
  PIN s_d1[11]
    DIRECTION OUTPUT ;
    USE SIGNAL ;
    ANTENNADIFFAREA 0.383400 ;
    PORT
      LAYER met2 ;
        RECT 505.630 0.000 505.910 0.280 ;
    END
  END s_d1[11]
  PIN s_d1[12]
    DIRECTION OUTPUT ;
    USE SIGNAL ;
    ANTENNADIFFAREA 0.383400 ;
    PORT
      LAYER met2 ;
        RECT 507.930 0.000 508.210 0.280 ;
    END
  END s_d1[12]
  PIN s_d1[13]
    DIRECTION OUTPUT ;
    USE SIGNAL ;
    ANTENNADIFFAREA 0.383400 ;
    PORT
      LAYER met2 ;
        RECT 510.230 0.000 510.510 0.280 ;
    END
  END s_d1[13]
  PIN s_d1[14]
    DIRECTION OUTPUT ;
    USE SIGNAL ;
    ANTENNADIFFAREA 0.383400 ;
    PORT
      LAYER met2 ;
        RECT 512.530 0.000 512.810 0.280 ;
    END
  END s_d1[14]
  PIN s_d1[15]
    DIRECTION OUTPUT ;
    USE SIGNAL ;
    ANTENNADIFFAREA 0.383400 ;
    PORT
      LAYER met2 ;
        RECT 514.830 0.000 515.110 0.280 ;
    END
  END s_d1[15]
  PIN s_d1[16]
    DIRECTION OUTPUT ;
    USE SIGNAL ;
    ANTENNADIFFAREA 0.383400 ;
    PORT
      LAYER met2 ;
        RECT 517.130 0.000 517.410 0.280 ;
    END
  END s_d1[16]
  PIN s_d1[17]
    DIRECTION OUTPUT ;
    USE SIGNAL ;
    ANTENNADIFFAREA 0.383400 ;
    PORT
      LAYER met2 ;
        RECT 519.430 0.000 519.710 0.280 ;
    END
  END s_d1[17]
  PIN s_d1[18]
    DIRECTION OUTPUT ;
    USE SIGNAL ;
    ANTENNADIFFAREA 0.383400 ;
    PORT
      LAYER met2 ;
        RECT 521.730 0.000 522.010 0.280 ;
    END
  END s_d1[18]
  PIN s_d1[19]
    DIRECTION OUTPUT ;
    USE SIGNAL ;
    ANTENNADIFFAREA 0.383400 ;
    PORT
      LAYER met2 ;
        RECT 524.030 0.000 524.310 0.280 ;
    END
  END s_d1[19]
  PIN s_d1[1]
    DIRECTION OUTPUT ;
    USE SIGNAL ;
    ANTENNADIFFAREA 0.383400 ;
    PORT
      LAYER met2 ;
        RECT 482.630 0.000 482.910 0.280 ;
    END
  END s_d1[1]
  PIN s_d1[20]
    DIRECTION OUTPUT ;
    USE SIGNAL ;
    ANTENNADIFFAREA 0.383400 ;
    PORT
      LAYER met2 ;
        RECT 526.330 0.000 526.610 0.280 ;
    END
  END s_d1[20]
  PIN s_d1[21]
    DIRECTION OUTPUT ;
    USE SIGNAL ;
    ANTENNADIFFAREA 0.383400 ;
    PORT
      LAYER met2 ;
        RECT 528.630 0.000 528.910 0.280 ;
    END
  END s_d1[21]
  PIN s_d1[22]
    DIRECTION OUTPUT ;
    USE SIGNAL ;
    ANTENNADIFFAREA 0.383400 ;
    PORT
      LAYER met2 ;
        RECT 530.930 0.000 531.210 0.280 ;
    END
  END s_d1[22]
  PIN s_d1[23]
    DIRECTION OUTPUT ;
    USE SIGNAL ;
    ANTENNADIFFAREA 0.383400 ;
    PORT
      LAYER met2 ;
        RECT 533.230 0.000 533.510 0.280 ;
    END
  END s_d1[23]
  PIN s_d1[24]
    DIRECTION OUTPUT ;
    USE SIGNAL ;
    ANTENNADIFFAREA 0.383400 ;
    PORT
      LAYER met2 ;
        RECT 535.530 0.000 535.810 0.280 ;
    END
  END s_d1[24]
  PIN s_d1[25]
    DIRECTION OUTPUT ;
    USE SIGNAL ;
    ANTENNADIFFAREA 0.383400 ;
    PORT
      LAYER met2 ;
        RECT 537.830 0.000 538.110 0.280 ;
    END
  END s_d1[25]
  PIN s_d1[26]
    DIRECTION OUTPUT ;
    USE SIGNAL ;
    ANTENNADIFFAREA 0.383400 ;
    PORT
      LAYER met2 ;
        RECT 540.130 0.000 540.410 0.280 ;
    END
  END s_d1[26]
  PIN s_d1[27]
    DIRECTION OUTPUT ;
    USE SIGNAL ;
    ANTENNADIFFAREA 0.383400 ;
    PORT
      LAYER met2 ;
        RECT 542.430 0.000 542.710 0.280 ;
    END
  END s_d1[27]
  PIN s_d1[28]
    DIRECTION OUTPUT ;
    USE SIGNAL ;
    ANTENNADIFFAREA 0.383400 ;
    PORT
      LAYER met2 ;
        RECT 544.730 0.000 545.010 0.280 ;
    END
  END s_d1[28]
  PIN s_d1[29]
    DIRECTION OUTPUT ;
    USE SIGNAL ;
    ANTENNADIFFAREA 0.383400 ;
    PORT
      LAYER met2 ;
        RECT 547.030 0.000 547.310 0.280 ;
    END
  END s_d1[29]
  PIN s_d1[2]
    DIRECTION OUTPUT ;
    USE SIGNAL ;
    ANTENNADIFFAREA 0.383400 ;
    PORT
      LAYER met2 ;
        RECT 484.930 0.000 485.210 0.280 ;
    END
  END s_d1[2]
  PIN s_d1[30]
    DIRECTION OUTPUT ;
    USE SIGNAL ;
    ANTENNADIFFAREA 0.383400 ;
    PORT
      LAYER met2 ;
        RECT 549.330 0.000 549.610 0.280 ;
    END
  END s_d1[30]
  PIN s_d1[31]
    DIRECTION OUTPUT ;
    USE SIGNAL ;
    ANTENNADIFFAREA 0.383400 ;
    PORT
      LAYER met2 ;
        RECT 551.630 0.000 551.910 0.280 ;
    END
  END s_d1[31]
  PIN s_d1[3]
    DIRECTION OUTPUT ;
    USE SIGNAL ;
    ANTENNADIFFAREA 0.383400 ;
    PORT
      LAYER met2 ;
        RECT 487.230 0.000 487.510 0.280 ;
    END
  END s_d1[3]
  PIN s_d1[4]
    DIRECTION OUTPUT ;
    USE SIGNAL ;
    ANTENNADIFFAREA 0.383400 ;
    PORT
      LAYER met2 ;
        RECT 489.530 0.000 489.810 0.280 ;
    END
  END s_d1[4]
  PIN s_d1[5]
    DIRECTION OUTPUT ;
    USE SIGNAL ;
    ANTENNADIFFAREA 0.383400 ;
    PORT
      LAYER met2 ;
        RECT 491.830 0.000 492.110 0.280 ;
    END
  END s_d1[5]
  PIN s_d1[6]
    DIRECTION OUTPUT ;
    USE SIGNAL ;
    ANTENNADIFFAREA 0.383400 ;
    PORT
      LAYER met2 ;
        RECT 494.130 0.000 494.410 0.280 ;
    END
  END s_d1[6]
  PIN s_d1[7]
    DIRECTION OUTPUT ;
    USE SIGNAL ;
    ANTENNADIFFAREA 0.383400 ;
    PORT
      LAYER met2 ;
        RECT 496.430 0.000 496.710 0.280 ;
    END
  END s_d1[7]
  PIN s_d1[8]
    DIRECTION OUTPUT ;
    USE SIGNAL ;
    ANTENNADIFFAREA 0.383400 ;
    PORT
      LAYER met2 ;
        RECT 498.730 0.000 499.010 0.280 ;
    END
  END s_d1[8]
  PIN s_d1[9]
    DIRECTION OUTPUT ;
    USE SIGNAL ;
    ANTENNADIFFAREA 0.383400 ;
    PORT
      LAYER met2 ;
        RECT 501.030 0.000 501.310 0.280 ;
    END
  END s_d1[9]
  PIN s_kind[0]
    DIRECTION OUTPUT ;
    USE SIGNAL ;
    ANTENNADIFFAREA 0.383400 ;
    PORT
      LAYER met2 ;
        RECT 402.130 0.000 402.410 0.280 ;
    END
  END s_kind[0]
  PIN s_kind[1]
    DIRECTION OUTPUT ;
    USE SIGNAL ;
    ANTENNADIFFAREA 0.383400 ;
    PORT
      LAYER met2 ;
        RECT 404.430 0.000 404.710 0.280 ;
    END
  END s_kind[1]
  PIN s_ready
    DIRECTION INPUT ;
    USE SIGNAL ;
    ANTENNAGATEAREA 0.196500 ;
    PORT
      LAYER met2 ;
        RECT 553.930 0.000 554.210 0.280 ;
    END
  END s_ready
  PIN s_valid
    DIRECTION OUTPUT ;
    USE SIGNAL ;
    ANTENNADIFFAREA 0.383400 ;
    PORT
      LAYER met2 ;
        RECT 399.830 0.000 400.110 0.280 ;
    END
  END s_valid
  PIN w_p0[0]
    DIRECTION INPUT ;
    USE SIGNAL ;
    ANTENNAGATEAREA 0.213000 ;
    PORT
      LAYER met3 ;
        RECT 0.000 448.840 0.600 449.440 ;
    END
  END w_p0[0]
  PIN w_p0[10]
    DIRECTION INPUT ;
    USE SIGNAL ;
    ANTENNAGATEAREA 0.213000 ;
    PORT
      LAYER met3 ;
        RECT 0.000 462.440 0.600 463.040 ;
    END
  END w_p0[10]
  PIN w_p0[11]
    DIRECTION INPUT ;
    USE SIGNAL ;
    ANTENNAGATEAREA 0.213000 ;
    PORT
      LAYER met3 ;
        RECT 0.000 463.800 0.600 464.400 ;
    END
  END w_p0[11]
  PIN w_p0[12]
    DIRECTION INPUT ;
    USE SIGNAL ;
    ANTENNAGATEAREA 0.213000 ;
    PORT
      LAYER met3 ;
        RECT 0.000 465.160 0.600 465.760 ;
    END
  END w_p0[12]
  PIN w_p0[13]
    DIRECTION INPUT ;
    USE SIGNAL ;
    ANTENNAGATEAREA 0.213000 ;
    PORT
      LAYER met3 ;
        RECT 0.000 466.520 0.600 467.120 ;
    END
  END w_p0[13]
  PIN w_p0[14]
    DIRECTION INPUT ;
    USE SIGNAL ;
    ANTENNAGATEAREA 0.213000 ;
    PORT
      LAYER met3 ;
        RECT 0.000 467.880 0.600 468.480 ;
    END
  END w_p0[14]
  PIN w_p0[15]
    DIRECTION INPUT ;
    USE SIGNAL ;
    ANTENNAGATEAREA 0.213000 ;
    PORT
      LAYER met3 ;
        RECT 0.000 469.240 0.600 469.840 ;
    END
  END w_p0[15]
  PIN w_p0[16]
    DIRECTION INPUT ;
    USE SIGNAL ;
    ANTENNAGATEAREA 0.213000 ;
    PORT
      LAYER met3 ;
        RECT 0.000 470.600 0.600 471.200 ;
    END
  END w_p0[16]
  PIN w_p0[17]
    DIRECTION INPUT ;
    USE SIGNAL ;
    ANTENNAGATEAREA 0.213000 ;
    PORT
      LAYER met3 ;
        RECT 0.000 471.960 0.600 472.560 ;
    END
  END w_p0[17]
  PIN w_p0[18]
    DIRECTION INPUT ;
    USE SIGNAL ;
    ANTENNAGATEAREA 0.213000 ;
    PORT
      LAYER met3 ;
        RECT 0.000 473.320 0.600 473.920 ;
    END
  END w_p0[18]
  PIN w_p0[19]
    DIRECTION INPUT ;
    USE SIGNAL ;
    ANTENNAGATEAREA 0.213000 ;
    PORT
      LAYER met3 ;
        RECT 0.000 474.680 0.600 475.280 ;
    END
  END w_p0[19]
  PIN w_p0[1]
    DIRECTION INPUT ;
    USE SIGNAL ;
    ANTENNAGATEAREA 0.213000 ;
    PORT
      LAYER met3 ;
        RECT 0.000 450.200 0.600 450.800 ;
    END
  END w_p0[1]
  PIN w_p0[20]
    DIRECTION INPUT ;
    USE SIGNAL ;
    ANTENNAGATEAREA 0.213000 ;
    PORT
      LAYER met3 ;
        RECT 0.000 476.040 0.600 476.640 ;
    END
  END w_p0[20]
  PIN w_p0[21]
    DIRECTION INPUT ;
    USE SIGNAL ;
    ANTENNAGATEAREA 0.213000 ;
    PORT
      LAYER met3 ;
        RECT 0.000 477.400 0.600 478.000 ;
    END
  END w_p0[21]
  PIN w_p0[22]
    DIRECTION INPUT ;
    USE SIGNAL ;
    ANTENNAGATEAREA 0.213000 ;
    PORT
      LAYER met3 ;
        RECT 0.000 478.760 0.600 479.360 ;
    END
  END w_p0[22]
  PIN w_p0[23]
    DIRECTION INPUT ;
    USE SIGNAL ;
    ANTENNAGATEAREA 0.213000 ;
    PORT
      LAYER met3 ;
        RECT 0.000 480.120 0.600 480.720 ;
    END
  END w_p0[23]
  PIN w_p0[24]
    DIRECTION INPUT ;
    USE SIGNAL ;
    ANTENNAGATEAREA 0.213000 ;
    PORT
      LAYER met3 ;
        RECT 0.000 481.480 0.600 482.080 ;
    END
  END w_p0[24]
  PIN w_p0[25]
    DIRECTION INPUT ;
    USE SIGNAL ;
    ANTENNAGATEAREA 0.213000 ;
    PORT
      LAYER met3 ;
        RECT 0.000 482.840 0.600 483.440 ;
    END
  END w_p0[25]
  PIN w_p0[26]
    DIRECTION INPUT ;
    USE SIGNAL ;
    ANTENNAGATEAREA 0.213000 ;
    PORT
      LAYER met3 ;
        RECT 0.000 484.200 0.600 484.800 ;
    END
  END w_p0[26]
  PIN w_p0[27]
    DIRECTION INPUT ;
    USE SIGNAL ;
    ANTENNAGATEAREA 0.213000 ;
    PORT
      LAYER met3 ;
        RECT 0.000 485.560 0.600 486.160 ;
    END
  END w_p0[27]
  PIN w_p0[28]
    DIRECTION INPUT ;
    USE SIGNAL ;
    ANTENNAGATEAREA 0.213000 ;
    PORT
      LAYER met3 ;
        RECT 0.000 486.920 0.600 487.520 ;
    END
  END w_p0[28]
  PIN w_p0[29]
    DIRECTION INPUT ;
    USE SIGNAL ;
    ANTENNAGATEAREA 0.213000 ;
    PORT
      LAYER met3 ;
        RECT 0.000 488.280 0.600 488.880 ;
    END
  END w_p0[29]
  PIN w_p0[2]
    DIRECTION INPUT ;
    USE SIGNAL ;
    ANTENNAGATEAREA 0.213000 ;
    PORT
      LAYER met3 ;
        RECT 0.000 451.560 0.600 452.160 ;
    END
  END w_p0[2]
  PIN w_p0[30]
    DIRECTION INPUT ;
    USE SIGNAL ;
    ANTENNAGATEAREA 0.213000 ;
    PORT
      LAYER met3 ;
        RECT 0.000 489.640 0.600 490.240 ;
    END
  END w_p0[30]
  PIN w_p0[31]
    DIRECTION INPUT ;
    USE SIGNAL ;
    ANTENNAGATEAREA 0.213000 ;
    PORT
      LAYER met3 ;
        RECT 0.000 491.000 0.600 491.600 ;
    END
  END w_p0[31]
  PIN w_p0[3]
    DIRECTION INPUT ;
    USE SIGNAL ;
    ANTENNAGATEAREA 0.213000 ;
    PORT
      LAYER met3 ;
        RECT 0.000 452.920 0.600 453.520 ;
    END
  END w_p0[3]
  PIN w_p0[4]
    DIRECTION INPUT ;
    USE SIGNAL ;
    ANTENNAGATEAREA 0.213000 ;
    PORT
      LAYER met3 ;
        RECT 0.000 454.280 0.600 454.880 ;
    END
  END w_p0[4]
  PIN w_p0[5]
    DIRECTION INPUT ;
    USE SIGNAL ;
    ANTENNAGATEAREA 0.213000 ;
    PORT
      LAYER met3 ;
        RECT 0.000 455.640 0.600 456.240 ;
    END
  END w_p0[5]
  PIN w_p0[6]
    DIRECTION INPUT ;
    USE SIGNAL ;
    ANTENNAGATEAREA 0.213000 ;
    PORT
      LAYER met3 ;
        RECT 0.000 457.000 0.600 457.600 ;
    END
  END w_p0[6]
  PIN w_p0[7]
    DIRECTION INPUT ;
    USE SIGNAL ;
    ANTENNAGATEAREA 0.213000 ;
    PORT
      LAYER met3 ;
        RECT 0.000 458.360 0.600 458.960 ;
    END
  END w_p0[7]
  PIN w_p0[8]
    DIRECTION INPUT ;
    USE SIGNAL ;
    ANTENNAGATEAREA 0.213000 ;
    PORT
      LAYER met3 ;
        RECT 0.000 459.720 0.600 460.320 ;
    END
  END w_p0[8]
  PIN w_p0[9]
    DIRECTION INPUT ;
    USE SIGNAL ;
    ANTENNAGATEAREA 0.213000 ;
    PORT
      LAYER met3 ;
        RECT 0.000 461.080 0.600 461.680 ;
    END
  END w_p0[9]
  PIN w_p1[0]
    DIRECTION INPUT ;
    USE SIGNAL ;
    ANTENNAGATEAREA 0.213000 ;
    PORT
      LAYER met3 ;
        RECT 0.000 492.360 0.600 492.960 ;
    END
  END w_p1[0]
  PIN w_p1[10]
    DIRECTION INPUT ;
    USE SIGNAL ;
    ANTENNAGATEAREA 0.213000 ;
    PORT
      LAYER met3 ;
        RECT 0.000 505.960 0.600 506.560 ;
    END
  END w_p1[10]
  PIN w_p1[11]
    DIRECTION INPUT ;
    USE SIGNAL ;
    ANTENNAGATEAREA 0.213000 ;
    PORT
      LAYER met3 ;
        RECT 0.000 507.320 0.600 507.920 ;
    END
  END w_p1[11]
  PIN w_p1[12]
    DIRECTION INPUT ;
    USE SIGNAL ;
    ANTENNAGATEAREA 0.213000 ;
    PORT
      LAYER met3 ;
        RECT 0.000 508.680 0.600 509.280 ;
    END
  END w_p1[12]
  PIN w_p1[13]
    DIRECTION INPUT ;
    USE SIGNAL ;
    ANTENNAGATEAREA 0.213000 ;
    PORT
      LAYER met3 ;
        RECT 0.000 510.040 0.600 510.640 ;
    END
  END w_p1[13]
  PIN w_p1[14]
    DIRECTION INPUT ;
    USE SIGNAL ;
    ANTENNAGATEAREA 0.213000 ;
    PORT
      LAYER met3 ;
        RECT 0.000 511.400 0.600 512.000 ;
    END
  END w_p1[14]
  PIN w_p1[15]
    DIRECTION INPUT ;
    USE SIGNAL ;
    ANTENNAGATEAREA 0.213000 ;
    PORT
      LAYER met3 ;
        RECT 0.000 512.760 0.600 513.360 ;
    END
  END w_p1[15]
  PIN w_p1[16]
    DIRECTION INPUT ;
    USE SIGNAL ;
    ANTENNAGATEAREA 0.213000 ;
    PORT
      LAYER met3 ;
        RECT 0.000 514.120 0.600 514.720 ;
    END
  END w_p1[16]
  PIN w_p1[17]
    DIRECTION INPUT ;
    USE SIGNAL ;
    ANTENNAGATEAREA 0.213000 ;
    PORT
      LAYER met3 ;
        RECT 0.000 515.480 0.600 516.080 ;
    END
  END w_p1[17]
  PIN w_p1[18]
    DIRECTION INPUT ;
    USE SIGNAL ;
    ANTENNAGATEAREA 0.213000 ;
    PORT
      LAYER met3 ;
        RECT 0.000 516.840 0.600 517.440 ;
    END
  END w_p1[18]
  PIN w_p1[19]
    DIRECTION INPUT ;
    USE SIGNAL ;
    ANTENNAGATEAREA 0.213000 ;
    PORT
      LAYER met3 ;
        RECT 0.000 518.200 0.600 518.800 ;
    END
  END w_p1[19]
  PIN w_p1[1]
    DIRECTION INPUT ;
    USE SIGNAL ;
    ANTENNAGATEAREA 0.213000 ;
    PORT
      LAYER met3 ;
        RECT 0.000 493.720 0.600 494.320 ;
    END
  END w_p1[1]
  PIN w_p1[20]
    DIRECTION INPUT ;
    USE SIGNAL ;
    ANTENNAGATEAREA 0.213000 ;
    PORT
      LAYER met3 ;
        RECT 0.000 519.560 0.600 520.160 ;
    END
  END w_p1[20]
  PIN w_p1[21]
    DIRECTION INPUT ;
    USE SIGNAL ;
    ANTENNAGATEAREA 0.213000 ;
    PORT
      LAYER met3 ;
        RECT 0.000 520.920 0.600 521.520 ;
    END
  END w_p1[21]
  PIN w_p1[22]
    DIRECTION INPUT ;
    USE SIGNAL ;
    ANTENNAGATEAREA 0.213000 ;
    PORT
      LAYER met3 ;
        RECT 0.000 522.280 0.600 522.880 ;
    END
  END w_p1[22]
  PIN w_p1[23]
    DIRECTION INPUT ;
    USE SIGNAL ;
    ANTENNAGATEAREA 0.213000 ;
    PORT
      LAYER met3 ;
        RECT 0.000 523.640 0.600 524.240 ;
    END
  END w_p1[23]
  PIN w_p1[24]
    DIRECTION INPUT ;
    USE SIGNAL ;
    ANTENNAGATEAREA 0.213000 ;
    PORT
      LAYER met3 ;
        RECT 0.000 525.000 0.600 525.600 ;
    END
  END w_p1[24]
  PIN w_p1[25]
    DIRECTION INPUT ;
    USE SIGNAL ;
    ANTENNAGATEAREA 0.213000 ;
    PORT
      LAYER met3 ;
        RECT 0.000 526.360 0.600 526.960 ;
    END
  END w_p1[25]
  PIN w_p1[26]
    DIRECTION INPUT ;
    USE SIGNAL ;
    ANTENNAGATEAREA 0.213000 ;
    PORT
      LAYER met3 ;
        RECT 0.000 527.720 0.600 528.320 ;
    END
  END w_p1[26]
  PIN w_p1[27]
    DIRECTION INPUT ;
    USE SIGNAL ;
    ANTENNAGATEAREA 0.213000 ;
    PORT
      LAYER met3 ;
        RECT 0.000 529.080 0.600 529.680 ;
    END
  END w_p1[27]
  PIN w_p1[28]
    DIRECTION INPUT ;
    USE SIGNAL ;
    ANTENNAGATEAREA 0.213000 ;
    PORT
      LAYER met3 ;
        RECT 0.000 530.440 0.600 531.040 ;
    END
  END w_p1[28]
  PIN w_p1[29]
    DIRECTION INPUT ;
    USE SIGNAL ;
    ANTENNAGATEAREA 0.213000 ;
    PORT
      LAYER met3 ;
        RECT 0.000 531.800 0.600 532.400 ;
    END
  END w_p1[29]
  PIN w_p1[2]
    DIRECTION INPUT ;
    USE SIGNAL ;
    ANTENNAGATEAREA 0.213000 ;
    PORT
      LAYER met3 ;
        RECT 0.000 495.080 0.600 495.680 ;
    END
  END w_p1[2]
  PIN w_p1[30]
    DIRECTION INPUT ;
    USE SIGNAL ;
    ANTENNAGATEAREA 0.213000 ;
    PORT
      LAYER met3 ;
        RECT 0.000 533.160 0.600 533.760 ;
    END
  END w_p1[30]
  PIN w_p1[31]
    DIRECTION INPUT ;
    USE SIGNAL ;
    ANTENNAGATEAREA 0.213000 ;
    PORT
      LAYER met3 ;
        RECT 0.000 534.520 0.600 535.120 ;
    END
  END w_p1[31]
  PIN w_p1[3]
    DIRECTION INPUT ;
    USE SIGNAL ;
    ANTENNAGATEAREA 0.213000 ;
    PORT
      LAYER met3 ;
        RECT 0.000 496.440 0.600 497.040 ;
    END
  END w_p1[3]
  PIN w_p1[4]
    DIRECTION INPUT ;
    USE SIGNAL ;
    ANTENNAGATEAREA 0.213000 ;
    PORT
      LAYER met3 ;
        RECT 0.000 497.800 0.600 498.400 ;
    END
  END w_p1[4]
  PIN w_p1[5]
    DIRECTION INPUT ;
    USE SIGNAL ;
    ANTENNAGATEAREA 0.213000 ;
    PORT
      LAYER met3 ;
        RECT 0.000 499.160 0.600 499.760 ;
    END
  END w_p1[5]
  PIN w_p1[6]
    DIRECTION INPUT ;
    USE SIGNAL ;
    ANTENNAGATEAREA 0.213000 ;
    PORT
      LAYER met3 ;
        RECT 0.000 500.520 0.600 501.120 ;
    END
  END w_p1[6]
  PIN w_p1[7]
    DIRECTION INPUT ;
    USE SIGNAL ;
    ANTENNAGATEAREA 0.213000 ;
    PORT
      LAYER met3 ;
        RECT 0.000 501.880 0.600 502.480 ;
    END
  END w_p1[7]
  PIN w_p1[8]
    DIRECTION INPUT ;
    USE SIGNAL ;
    ANTENNAGATEAREA 0.213000 ;
    PORT
      LAYER met3 ;
        RECT 0.000 503.240 0.600 503.840 ;
    END
  END w_p1[8]
  PIN w_p1[9]
    DIRECTION INPUT ;
    USE SIGNAL ;
    ANTENNAGATEAREA 0.213000 ;
    PORT
      LAYER met3 ;
        RECT 0.000 504.600 0.600 505.200 ;
    END
  END w_p1[9]
  PIN w_ready
    DIRECTION OUTPUT ;
    USE SIGNAL ;
    ANTENNADIFFAREA 0.383400 ;
    PORT
      LAYER met3 ;
        RECT 0.000 535.880 0.600 536.480 ;
    END
  END w_ready
  PIN w_valid
    DIRECTION INPUT ;
    USE SIGNAL ;
    ANTENNAGATEAREA 0.213000 ;
    PORT
      LAYER met3 ;
        RECT 0.000 447.480 0.600 448.080 ;
    END
  END w_valid
  OBS
      LAYER nwell ;
        RECT 5.330 10.795 953.310 973.845 ;
      LAYER li1 ;
        RECT 5.520 10.795 953.120 973.845 ;
      LAYER met1 ;
        RECT 1.450 10.240 953.120 974.000 ;
      LAYER met2 ;
        RECT 1.470 984.440 399.550 984.720 ;
        RECT 400.390 984.440 401.850 984.720 ;
        RECT 402.690 984.440 404.150 984.720 ;
        RECT 404.990 984.440 406.450 984.720 ;
        RECT 407.290 984.440 408.750 984.720 ;
        RECT 409.590 984.440 411.050 984.720 ;
        RECT 411.890 984.440 413.350 984.720 ;
        RECT 414.190 984.440 415.650 984.720 ;
        RECT 416.490 984.440 417.950 984.720 ;
        RECT 418.790 984.440 420.250 984.720 ;
        RECT 421.090 984.440 422.550 984.720 ;
        RECT 423.390 984.440 424.850 984.720 ;
        RECT 425.690 984.440 427.150 984.720 ;
        RECT 427.990 984.440 429.450 984.720 ;
        RECT 430.290 984.440 431.750 984.720 ;
        RECT 432.590 984.440 434.050 984.720 ;
        RECT 434.890 984.440 436.350 984.720 ;
        RECT 437.190 984.440 438.650 984.720 ;
        RECT 439.490 984.440 440.950 984.720 ;
        RECT 441.790 984.440 443.250 984.720 ;
        RECT 444.090 984.440 445.550 984.720 ;
        RECT 446.390 984.440 447.850 984.720 ;
        RECT 448.690 984.440 450.150 984.720 ;
        RECT 450.990 984.440 452.450 984.720 ;
        RECT 453.290 984.440 454.750 984.720 ;
        RECT 455.590 984.440 457.050 984.720 ;
        RECT 457.890 984.440 459.350 984.720 ;
        RECT 460.190 984.440 461.650 984.720 ;
        RECT 462.490 984.440 463.950 984.720 ;
        RECT 464.790 984.440 466.250 984.720 ;
        RECT 467.090 984.440 468.550 984.720 ;
        RECT 469.390 984.440 470.850 984.720 ;
        RECT 471.690 984.440 473.150 984.720 ;
        RECT 473.990 984.440 475.450 984.720 ;
        RECT 476.290 984.440 477.750 984.720 ;
        RECT 478.590 984.440 480.050 984.720 ;
        RECT 480.890 984.440 482.350 984.720 ;
        RECT 483.190 984.440 484.650 984.720 ;
        RECT 485.490 984.440 486.950 984.720 ;
        RECT 487.790 984.440 489.250 984.720 ;
        RECT 490.090 984.440 491.550 984.720 ;
        RECT 492.390 984.440 493.850 984.720 ;
        RECT 494.690 984.440 496.150 984.720 ;
        RECT 496.990 984.440 498.450 984.720 ;
        RECT 499.290 984.440 500.750 984.720 ;
        RECT 501.590 984.440 503.050 984.720 ;
        RECT 503.890 984.440 505.350 984.720 ;
        RECT 506.190 984.440 507.650 984.720 ;
        RECT 508.490 984.440 509.950 984.720 ;
        RECT 510.790 984.440 512.250 984.720 ;
        RECT 513.090 984.440 514.550 984.720 ;
        RECT 515.390 984.440 516.850 984.720 ;
        RECT 517.690 984.440 519.150 984.720 ;
        RECT 519.990 984.440 521.450 984.720 ;
        RECT 522.290 984.440 523.750 984.720 ;
        RECT 524.590 984.440 526.050 984.720 ;
        RECT 526.890 984.440 528.350 984.720 ;
        RECT 529.190 984.440 530.650 984.720 ;
        RECT 531.490 984.440 532.950 984.720 ;
        RECT 533.790 984.440 535.250 984.720 ;
        RECT 536.090 984.440 537.550 984.720 ;
        RECT 538.390 984.440 539.850 984.720 ;
        RECT 540.690 984.440 542.150 984.720 ;
        RECT 542.990 984.440 544.450 984.720 ;
        RECT 545.290 984.440 546.750 984.720 ;
        RECT 547.590 984.440 549.050 984.720 ;
        RECT 549.890 984.440 551.350 984.720 ;
        RECT 552.190 984.440 553.650 984.720 ;
        RECT 554.490 984.440 951.650 984.720 ;
        RECT 1.470 0.560 951.650 984.440 ;
        RECT 1.470 0.280 399.550 0.560 ;
        RECT 400.390 0.280 401.850 0.560 ;
        RECT 402.690 0.280 404.150 0.560 ;
        RECT 404.990 0.280 406.450 0.560 ;
        RECT 407.290 0.280 408.750 0.560 ;
        RECT 409.590 0.280 411.050 0.560 ;
        RECT 411.890 0.280 413.350 0.560 ;
        RECT 414.190 0.280 415.650 0.560 ;
        RECT 416.490 0.280 417.950 0.560 ;
        RECT 418.790 0.280 420.250 0.560 ;
        RECT 421.090 0.280 422.550 0.560 ;
        RECT 423.390 0.280 424.850 0.560 ;
        RECT 425.690 0.280 427.150 0.560 ;
        RECT 427.990 0.280 429.450 0.560 ;
        RECT 430.290 0.280 431.750 0.560 ;
        RECT 432.590 0.280 434.050 0.560 ;
        RECT 434.890 0.280 436.350 0.560 ;
        RECT 437.190 0.280 438.650 0.560 ;
        RECT 439.490 0.280 440.950 0.560 ;
        RECT 441.790 0.280 443.250 0.560 ;
        RECT 444.090 0.280 445.550 0.560 ;
        RECT 446.390 0.280 447.850 0.560 ;
        RECT 448.690 0.280 450.150 0.560 ;
        RECT 450.990 0.280 452.450 0.560 ;
        RECT 453.290 0.280 454.750 0.560 ;
        RECT 455.590 0.280 457.050 0.560 ;
        RECT 457.890 0.280 459.350 0.560 ;
        RECT 460.190 0.280 461.650 0.560 ;
        RECT 462.490 0.280 463.950 0.560 ;
        RECT 464.790 0.280 466.250 0.560 ;
        RECT 467.090 0.280 468.550 0.560 ;
        RECT 469.390 0.280 470.850 0.560 ;
        RECT 471.690 0.280 473.150 0.560 ;
        RECT 473.990 0.280 475.450 0.560 ;
        RECT 476.290 0.280 477.750 0.560 ;
        RECT 478.590 0.280 480.050 0.560 ;
        RECT 480.890 0.280 482.350 0.560 ;
        RECT 483.190 0.280 484.650 0.560 ;
        RECT 485.490 0.280 486.950 0.560 ;
        RECT 487.790 0.280 489.250 0.560 ;
        RECT 490.090 0.280 491.550 0.560 ;
        RECT 492.390 0.280 493.850 0.560 ;
        RECT 494.690 0.280 496.150 0.560 ;
        RECT 496.990 0.280 498.450 0.560 ;
        RECT 499.290 0.280 500.750 0.560 ;
        RECT 501.590 0.280 503.050 0.560 ;
        RECT 503.890 0.280 505.350 0.560 ;
        RECT 506.190 0.280 507.650 0.560 ;
        RECT 508.490 0.280 509.950 0.560 ;
        RECT 510.790 0.280 512.250 0.560 ;
        RECT 513.090 0.280 514.550 0.560 ;
        RECT 515.390 0.280 516.850 0.560 ;
        RECT 517.690 0.280 519.150 0.560 ;
        RECT 519.990 0.280 521.450 0.560 ;
        RECT 522.290 0.280 523.750 0.560 ;
        RECT 524.590 0.280 526.050 0.560 ;
        RECT 526.890 0.280 528.350 0.560 ;
        RECT 529.190 0.280 530.650 0.560 ;
        RECT 531.490 0.280 532.950 0.560 ;
        RECT 533.790 0.280 535.250 0.560 ;
        RECT 536.090 0.280 537.550 0.560 ;
        RECT 538.390 0.280 539.850 0.560 ;
        RECT 540.690 0.280 542.150 0.560 ;
        RECT 542.990 0.280 544.450 0.560 ;
        RECT 545.290 0.280 546.750 0.560 ;
        RECT 547.590 0.280 549.050 0.560 ;
        RECT 549.890 0.280 551.350 0.560 ;
        RECT 552.190 0.280 553.650 0.560 ;
        RECT 554.490 0.280 555.950 0.560 ;
        RECT 556.790 0.280 558.250 0.560 ;
        RECT 559.090 0.280 951.650 0.560 ;
      LAYER met3 ;
        RECT 0.600 536.880 958.400 973.925 ;
        RECT 1.000 447.080 958.000 536.880 ;
        RECT 0.600 10.715 958.400 447.080 ;
      LAYER met4 ;
        RECT 75.735 914.125 174.240 914.160 ;
        RECT 176.640 914.125 177.540 914.160 ;
        RECT 179.940 914.125 327.840 914.160 ;
        RECT 330.240 914.125 331.140 914.160 ;
        RECT 333.540 914.125 481.440 914.160 ;
        RECT 75.735 615.195 481.440 914.125 ;
        RECT 75.735 369.445 174.240 615.195 ;
        RECT 176.640 369.445 177.540 615.195 ;
        RECT 179.940 369.445 327.840 615.195 ;
        RECT 330.240 369.445 331.140 615.195 ;
        RECT 333.540 369.445 481.440 615.195 ;
        RECT 75.735 70.515 481.440 369.445 ;
        RECT 75.735 19.895 174.240 70.515 ;
        RECT 176.640 19.895 177.540 70.515 ;
        RECT 179.940 19.895 327.840 70.515 ;
        RECT 330.240 19.895 331.140 70.515 ;
        RECT 333.540 19.895 481.440 70.515 ;
        RECT 483.840 19.895 484.740 914.160 ;
        RECT 487.140 914.125 635.040 914.160 ;
        RECT 637.440 914.125 638.340 914.160 ;
        RECT 640.740 914.125 788.640 914.160 ;
        RECT 791.040 914.125 791.940 914.160 ;
        RECT 794.340 914.125 883.365 914.160 ;
        RECT 487.140 615.195 883.365 914.125 ;
        RECT 487.140 369.445 635.040 615.195 ;
        RECT 637.440 369.445 638.340 615.195 ;
        RECT 640.740 369.445 788.640 615.195 ;
        RECT 791.040 369.445 791.940 615.195 ;
        RECT 794.340 369.445 883.365 615.195 ;
        RECT 487.140 70.515 883.365 369.445 ;
        RECT 487.140 19.895 635.040 70.515 ;
        RECT 637.440 19.895 638.340 70.515 ;
        RECT 640.740 19.895 788.640 70.515 ;
        RECT 791.040 19.895 791.940 70.515 ;
        RECT 794.340 19.895 883.365 70.515 ;
      LAYER met5 ;
        RECT 574.660 612.900 587.300 614.500 ;
  END
END jev_mesh_2x2
END LIBRARY

